VERSION 5.8 ;
BUSBITCHARS "[]" ;
DIVIDERCHAR "/" ;

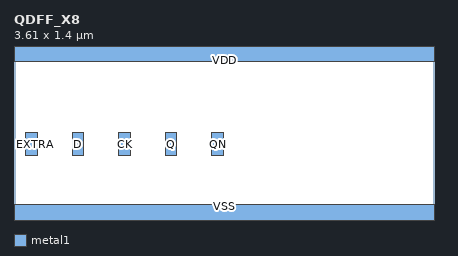
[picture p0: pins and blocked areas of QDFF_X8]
MACRO QDFF_X8
  CLASS CORE ;
  ORIGIN 0 0 ;
  FOREIGN QDFF_X8 0 0 ;
  SIZE 3.61 BY 1.4 ;
  SYMMETRY X Y ;
  SITE FreePDK45_38x28_10R_NP_162NW_34O ;
  PIN EXTRA
    DIRECTION INPUT ;
    USE SIGNAL ;
    PORT
      LAYER metal1 ;
        RECT 0.1 0.5 0.2 0.7 ;
    END
  END EXTRA
  PIN D
    DIRECTION INPUT ;
    USE SIGNAL ;
    PORT
      LAYER metal1 ;
        RECT 0.5 0.5 0.6 0.7 ;
    END
  END D
  PIN CK
    DIRECTION INPUT ;
    USE SIGNAL ;
    PORT
      LAYER metal1 ;
        RECT 0.9 0.5 1.0 0.7 ;
    END
  END CK
  PIN Q
    DIRECTION OUTPUT ;
    USE SIGNAL ;
    PORT
      LAYER metal1 ;
        RECT 1.3 0.5 1.4 0.7 ;
    END
  END Q
  PIN QN
    DIRECTION OUTPUT ;
    USE SIGNAL ;
    PORT
      LAYER metal1 ;
        RECT 1.7 0.5 1.8 0.7 ;
    END
  END QN
  PIN VDD
    DIRECTION INOUT ;
    USE POWER ;
    SHAPE ABUTMENT ;
    PORT
      LAYER metal1 ;
        RECT 0 1.315 3.61 1.485 ;
    END
  END VDD
  PIN VSS
    DIRECTION INOUT ;
    USE GROUND ;
    SHAPE ABUTMENT ;
    PORT
      LAYER metal1 ;
        RECT 0 -0.085 3.61 0.085 ;
    END
  END VSS
END QDFF_X8

END LIBRARY
